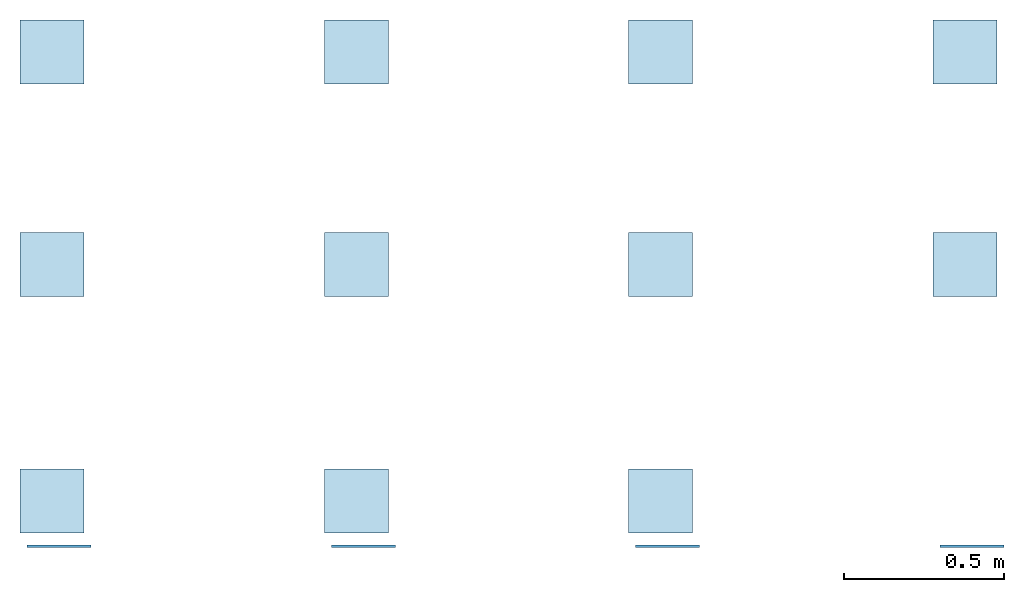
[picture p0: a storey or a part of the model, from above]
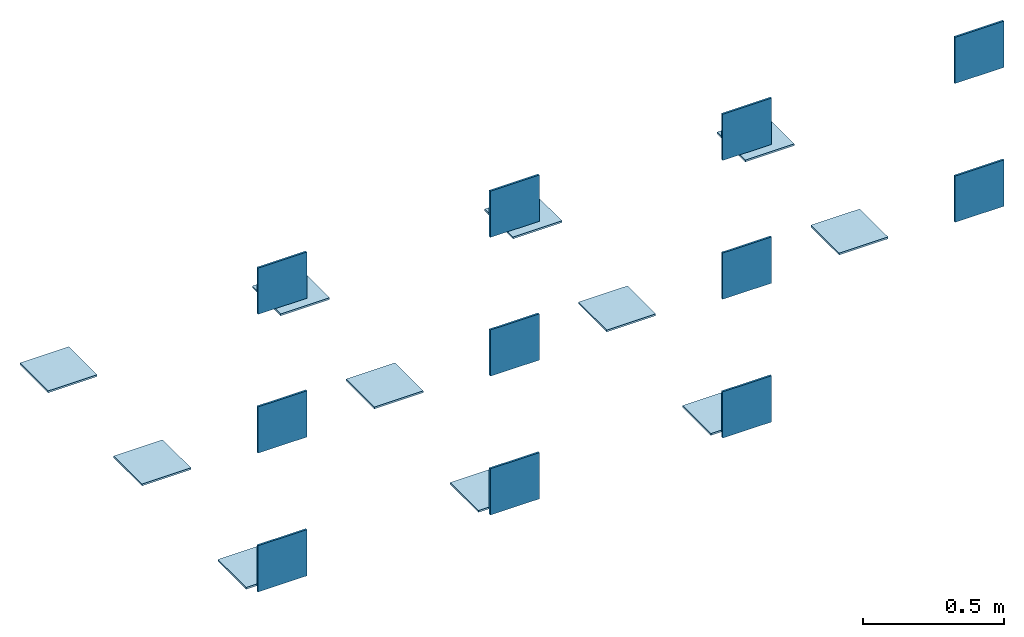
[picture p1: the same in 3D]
Properties of the parts of a building model (IFC2X3)

# File
Description: ViewDefinition [CoordinationView_V2.0]
File name: Número de proyecto
Time: 2019-02-18T09:29:20
Written by: The EXPRESS Data Manager Version 5.02.0100.07 : 28 Aug 2013
Made in: 20140606_1530(x64) - Exporter 15.7.0.0 - Alternate UI 15.7.0.0
Comment: STEP Physical File produced by: The EXPRESS Data Manager Version 5.02.0100.07 : 28 Aug 2013 * Module: EDMstepFileFactory/EDMstandAlone * Creation date: Mon Feb 18 09:29:20 2019 * Host: WEB2 * Database: C:\Users\webpc2\AppData\Local\Temp\{F0511C40-41A1-4CF2-A125-B7FABC9902E5}\ifc * Database version: 5507 * Database creation date: Mon Feb 18 09:29:19 2019 * Schema: IFC2X3 * Model: DataRepository.ifc * Model creation date: Mon Feb 18 09:29:19 2019 * Header model: DataRepository.ifc_HeaderModel * Header model creation date: Mon Feb 18 09:29:19 2019 * EDMuser: sdai-user * EDMgroup: sdai-group * License ID and type: 5605 : Permanent license. Expiry date: * EDMstepFileFactory options: 020000

# IfcProject, Número de proyecto
LongName: Nombre de proyecto; Phase: Estado de proyecto

# IfcSite, Default
RefLatitude: 40, 25, 0, 86975; RefLongitude: -3, -42, -1, -243858; RefElevation: 0 m

# IfcBuilding
Pset_BuildingCommon - NumberOfStoreys: 1

# IfcBuildingStorey, SVENSKA FLOOR TILES
LongName: SVENSKA FLOOR TILES; Elevation: 0 m

# IfcSlab: Suelo:VIVES - BLOMKNOPP BONE 20x20, Suelo:VIVES - BLOMKNOPP BONE 20x20:259942
In: SVENSKA FLOOR TILES
PredefinedType: FLOOR; Material: VIVES - BLOMKNOPP BONE 20x20 0.008 m
Pset_SlabCommon - Reference: VIVES - BLOMKNOPP BONE 20x20; IsExternal: no; LoadBearing: no; ThermalTransmittance: 187.5 kg/K/s3; PitchAngle: 0 deg
Pset_ManufacturerTypeInformation - Manufacturer: VIVES Azulejos y Gres S.A.

# IfcSlab: Suelo:VIVES - BLOMKNOPP SIENA 20x20, Suelo:VIVES - BLOMKNOPP SIENA 20x20:259982
In: SVENSKA FLOOR TILES
PredefinedType: FLOOR; Material: VIVES - BLOMKNOPP SIENA 20x20 0.008 m
Pset_SlabCommon - IsExternal: no; LoadBearing: no; PitchAngle: 0 deg; Reference: VIVES - BLOMKNOPP SIENA 20x20; ThermalTransmittance: 187.5 kg/K/s3
Pset_ManufacturerTypeInformation - Manufacturer: VIVES Azulejos y Gres S.A.

# IfcSlab: Suelo:VIVES - ETT 20x20, Suelo:VIVES - ETT 20x20:260022
In: SVENSKA FLOOR TILES
PredefinedType: FLOOR; Material: VIVES - ETT 20x20 0.008 m
Pset_SlabCommon - IsExternal: no; LoadBearing: no; PitchAngle: 0 deg; Reference: VIVES - ETT 20x20; ThermalTransmittance: 187.5 kg/K/s3
Pset_ManufacturerTypeInformation - Manufacturer: VIVES Azulejos y Gres S.A.

# IfcSlab: Suelo:VIVES - HALVMANE 20x20, Suelo:VIVES - HALVMANE 20x20:260062
In: SVENSKA FLOOR TILES
PredefinedType: FLOOR; Material: VIVES - HALVMANE 20x20 0.008 m
Pset_SlabCommon - IsExternal: no; LoadBearing: no; PitchAngle: 0 deg; Reference: VIVES - HALVMANE 20x20; ThermalTransmittance: 187.5 kg/K/s3
Pset_ManufacturerTypeInformation - Manufacturer: VIVES Azulejos y Gres S.A.

# IfcSlab: Suelo:VIVES - JOLEJON 20x20, Suelo:VIVES - JOLEJON 20x20:260102
In: SVENSKA FLOOR TILES
PredefinedType: FLOOR; Material: VIVES - JOLEJON 20x20 0.008 m
Pset_SlabCommon - IsExternal: no; LoadBearing: no; PitchAngle: 0 deg; Reference: VIVES - JOLEJON 20x20; ThermalTransmittance: 187.5 kg/K/s3
Pset_ManufacturerTypeInformation - Manufacturer: VIVES Azulejos y Gres S.A.

# IfcSlab: Suelo:VIVES - JUVEL 20x20, Suelo:VIVES - JUVEL 20x20:260142
In: SVENSKA FLOOR TILES
PredefinedType: FLOOR; Material: VIVES - JUVEL 20x20 0.008 m
Pset_SlabCommon - IsExternal: no; LoadBearing: no; PitchAngle: 0 deg; Reference: VIVES - JUVEL 20x20; ThermalTransmittance: 187.5 kg/K/s3
Pset_ManufacturerTypeInformation - Manufacturer: VIVES Azulejos y Gres S.A.

# IfcSlab: Suelo:VIVES - TRE ANTRACITA 20x20, Suelo:VIVES - TRE ANTRACITA 20x20:260222
In: SVENSKA FLOOR TILES
PredefinedType: FLOOR; Material: VIVES - TRE ANTRACITA 20x20 0.008 m
Pset_SlabCommon - IsExternal: no; LoadBearing: no; PitchAngle: 0 deg; Reference: VIVES - TRE ANTRACITA 20x20; ThermalTransmittance: 187.5 kg/K/s3
Pset_ManufacturerTypeInformation - Manufacturer: VIVES Azulejos y Gres S.A.

# IfcSlab: Suelo:VIVES - TRE HUMO 20x20, Suelo:VIVES - TRE HUMO 20x20:260262
In: SVENSKA FLOOR TILES
PredefinedType: FLOOR; Material: VIVES - TRE HUMO 20x20 0.008 m
Pset_SlabCommon - IsExternal: no; LoadBearing: no; PitchAngle: 0 deg; Reference: VIVES - TRE HUMO 20x20; ThermalTransmittance: 187.5 kg/K/s3
Pset_ManufacturerTypeInformation - Manufacturer: VIVES Azulejos y Gres S.A.

# IfcSlab: Suelo:VIVES - TRE JADE 20x20, Suelo:VIVES - TRE JADE 20x20:260302
In: SVENSKA FLOOR TILES
PredefinedType: FLOOR; Material: VIVES - TRE JADE 20x20 0.008 m
Pset_SlabCommon - IsExternal: no; LoadBearing: no; PitchAngle: 0 deg; Reference: VIVES - TRE JADE 20x20; ThermalTransmittance: 187.5 kg/K/s3
Pset_ManufacturerTypeInformation - Manufacturer: VIVES Azulejos y Gres S.A.

# IfcSlab: Suelo:VIVES - TRE NUBE 20x20, Suelo:VIVES - TRE NUBE 20x20:260342
In: SVENSKA FLOOR TILES
PredefinedType: FLOOR; Material: VIVES - TRE NUBE 20x20 0.008 m
Pset_SlabCommon - IsExternal: no; LoadBearing: no; PitchAngle: 0 deg; Reference: VIVES - TRE NUBE 20x20; ThermalTransmittance: 187.5 kg/K/s3
Pset_ManufacturerTypeInformation - Manufacturer: VIVES Azulejos y Gres S.A.

# IfcSlab: Suelo:VIVES - TULPAN 20x20, Suelo:VIVES - TULPAN 20x20:260182
In: SVENSKA FLOOR TILES
PredefinedType: FLOOR; Material: VIVES - TULPAN 20x20 0.008 m
Pset_SlabCommon - IsExternal: no; LoadBearing: no; PitchAngle: 0 deg; Reference: VIVES - TULPAN 20x20; ThermalTransmittance: 187.5 kg/K/s3
Pset_ManufacturerTypeInformation - Manufacturer: VIVES Azulejos y Gres S.A.

# IfcWallStandardCase: Muro básico:VIVES - BLOMKNOPP BONE 20x20, Muro básico:VIVES - BLOMKNOPP BONE 20x20:261192
In: SVENSKA FLOOR TILES
Type - PredefinedType: STANDARD; Material: VIVES - BLOMKNOPP BONE 20x20 0.008 m
Pset_WallCommon - Reference: VIVES - BLOMKNOPP BONE 20x20; IsExternal: no; LoadBearing: no; ExtendToStructure: no; ThermalTransmittance: 187.5 kg/K/s3
Pset_ManufacturerTypeInformation - Manufacturer: VIVES Azulejos y Gres S.A.

# IfcWallStandardCase: Muro básico:VIVES - BLOMKNOPP SIENA 20x20, Muro básico:VIVES - BLOMKNOPP SIENA 20x20:261193
In: SVENSKA FLOOR TILES
Type - PredefinedType: STANDARD; Material: VIVES - BLOMKNOPP SIENA 20x20 0.008 m
Pset_WallCommon - IsExternal: no; LoadBearing: no; Reference: VIVES - BLOMKNOPP SIENA 20x20; ExtendToStructure: no; ThermalTransmittance: 187.5 kg/K/s3
Pset_ManufacturerTypeInformation - Manufacturer: VIVES Azulejos y Gres S.A.

# IfcWallStandardCase: Muro básico:VIVES - ETT 20x20, Muro básico:VIVES - ETT 20x20:260012
In: SVENSKA FLOOR TILES
Type - PredefinedType: STANDARD; Material: VIVES - ETT 20x20 0.008 m
Pset_WallCommon - IsExternal: no; LoadBearing: no; Reference: VIVES - ETT 20x20; ExtendToStructure: no; ThermalTransmittance: 187.5 kg/K/s3
Pset_ManufacturerTypeInformation - Manufacturer: VIVES Azulejos y Gres S.A.

# IfcWallStandardCase: Muro básico:VIVES - HALVMANE 20x20, Muro básico:VIVES - HALVMANE 20x20:260052
In: SVENSKA FLOOR TILES
Type - PredefinedType: STANDARD; Material: VIVES - HALVMANE 20x20 0.008 m
Pset_WallCommon - IsExternal: no; LoadBearing: no; ExtendToStructure: no; Reference: VIVES - HALVMANE 20x20; ThermalTransmittance: 187.5 kg/K/s3
Pset_ManufacturerTypeInformation - Manufacturer: VIVES Azulejos y Gres S.A.

# IfcWallStandardCase: Muro básico:VIVES - JOLEJON 20x20, Muro básico:VIVES - JOLEJON 20x20:261194
In: SVENSKA FLOOR TILES
Type - PredefinedType: STANDARD; Material: VIVES - JOLEJON 20x20 0.008 m
Pset_WallCommon - IsExternal: no; LoadBearing: no; ExtendToStructure: no; Reference: VIVES - JOLEJON 20x20; ThermalTransmittance: 187.5 kg/K/s3
Pset_ManufacturerTypeInformation - Manufacturer: VIVES Azulejos y Gres S.A.

# IfcWallStandardCase: Muro básico:VIVES - JUVEL 20x20, Muro básico:VIVES - JUVEL 20x20:260132
In: SVENSKA FLOOR TILES
Type - PredefinedType: STANDARD; Material: VIVES - JUVEL 20x20 0.008 m
Pset_WallCommon - IsExternal: no; LoadBearing: no; ExtendToStructure: no; Reference: VIVES - JUVEL 20x20; ThermalTransmittance: 187.5 kg/K/s3
Pset_ManufacturerTypeInformation - Manufacturer: VIVES Azulejos y Gres S.A.

# IfcWallStandardCase: Muro básico:VIVES - TRE ANTRACITA 20x20, Muro básico:VIVES - TRE ANTRACITA 20x20:261089
In: SVENSKA FLOOR TILES
Type - PredefinedType: STANDARD; Material: VIVES - TRE ANTRACITA 20x20 0.008 m
Pset_WallCommon - IsExternal: no; LoadBearing: no; ExtendToStructure: no; Reference: VIVES - TRE ANTRACITA 20x20; ThermalTransmittance: 187.5 kg/K/s3
Pset_ManufacturerTypeInformation - Manufacturer: VIVES Azulejos y Gres S.A.

# IfcWallStandardCase: Muro básico:VIVES - TRE HUMO 20x20, Muro básico:VIVES - TRE HUMO 20x20:261090
In: SVENSKA FLOOR TILES
Type - PredefinedType: STANDARD; Material: VIVES - TRE HUMO 20x20 0.008 m
Pset_WallCommon - IsExternal: no; LoadBearing: no; ExtendToStructure: no; Reference: VIVES - TRE HUMO 20x20; ThermalTransmittance: 187.5 kg/K/s3
Pset_ManufacturerTypeInformation - Manufacturer: VIVES Azulejos y Gres S.A.

# IfcWallStandardCase: Muro básico:VIVES - TRE JADE 20x20, Muro básico:VIVES - TRE JADE 20x20:261091
In: SVENSKA FLOOR TILES
Type - PredefinedType: STANDARD; Material: VIVES - TRE JADE 20x20 0.008 m
Pset_WallCommon - IsExternal: no; LoadBearing: no; ExtendToStructure: no; Reference: VIVES - TRE JADE 20x20; ThermalTransmittance: 187.5 kg/K/s3
Pset_ManufacturerTypeInformation - Manufacturer: VIVES Azulejos y Gres S.A.

# IfcWallStandardCase: Muro básico:VIVES - TRE NUBE 20x20, Muro básico:VIVES - TRE NUBE 20x20:261092
In: SVENSKA FLOOR TILES
Type - PredefinedType: STANDARD; Material: VIVES - TRE NUBE 20x20 0.008 m
Pset_WallCommon - IsExternal: no; LoadBearing: no; ExtendToStructure: no; Reference: VIVES - TRE NUBE 20x20; ThermalTransmittance: 187.5 kg/K/s3
Pset_ManufacturerTypeInformation - Manufacturer: VIVES Azulejos y Gres S.A.

# IfcWallStandardCase: Muro básico:VIVES - TULPAN 20x20, Muro básico:VIVES - TULPAN 20x20:261195
In: SVENSKA FLOOR TILES
Type - PredefinedType: STANDARD; Material: VIVES - TULPAN 20x20 0.008 m
Pset_WallCommon - IsExternal: no; LoadBearing: no; ExtendToStructure: no; Reference: VIVES - TULPAN 20x20; ThermalTransmittance: 187.5 kg/K/s3
Pset_ManufacturerTypeInformation - Manufacturer: VIVES Azulejos y Gres S.A.
